VERSION 5.8 ;
BUSBITCHARS "[]" ;
DIVIDERCHAR "/" ;
UNITS
    DATABASE MICRONS 1000 ;
END UNITS

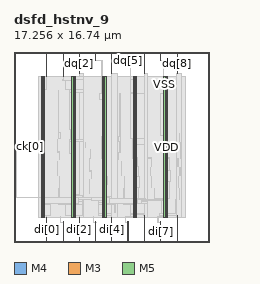
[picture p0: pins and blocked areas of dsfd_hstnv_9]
MACRO dsfd_hstnv_9
  FOREIGN dsfd_hstnv_9 0 0 ;
  CLASS BLOCK ;
  SIZE 17.256 BY 16.74 ;
  PIN ck[0]
    DIRECTION INPUT ;
    USE SIGNAL ;
    PORT
      LAYER M4 ;
        RECT  0 8.4 0.192 8.424 ;
    END
    PORT
      LAYER M4 ;
        RECT  0.156 8.4 0.275 8.424 ;
    END
  END ck[0]
  PIN di[0]
    DIRECTION INPUT ;
    USE SIGNAL ;
    PORT
      LAYER M3 ;
        RECT  2.88 0 2.898 0.144 ;
    END
    PORT
      LAYER M3 ;
        RECT  2.88 0.108 2.898 2.143 ;
    END
  END di[0]
  PIN di[1]
    DIRECTION INPUT ;
    USE SIGNAL ;
    PORT
      LAYER M5 ;
        RECT  4.32 0 4.344 0.192 ;
    END
    PORT
      LAYER M5 ;
        RECT  4.32 0.144 4.344 1.763 ;
    END
  END di[1]
  PIN di[2]
    DIRECTION INPUT ;
    USE SIGNAL ;
    PORT
      LAYER M3 ;
        RECT  5.76 0 5.778 0.144 ;
    END
    PORT
      LAYER M3 ;
        RECT  5.76 0.108 5.778 2.143 ;
    END
  END di[2]
  PIN di[3]
    DIRECTION INPUT ;
    USE SIGNAL ;
    PORT
      LAYER M5 ;
        RECT  7.2 0 7.224 0.192 ;
    END
    PORT
      LAYER M5 ;
        RECT  7.2 0.144 7.224 1.763 ;
    END
  END di[3]
  PIN di[4]
    DIRECTION INPUT ;
    USE SIGNAL ;
    PORT
      LAYER M3 ;
        RECT  8.604 0 8.622 0.144 ;
    END
    PORT
      LAYER M3 ;
        RECT  8.604 0.108 8.622 2.143 ;
    END
  END di[4]
  PIN di[5]
    DIRECTION INPUT ;
    USE SIGNAL ;
    PORT
      LAYER M5 ;
        RECT  10.032 0 10.056 0.192 ;
    END
    PORT
      LAYER M5 ;
        RECT  10.032 0.144 10.056 1.763 ;
    END
  END di[5]
  PIN di[6]
    DIRECTION INPUT ;
    USE SIGNAL ;
    PORT
      LAYER M3 ;
        RECT  11.484 0 11.502 0.144 ;
    END
    PORT
      LAYER M3 ;
        RECT  11.484 0.108 11.502 2.371 ;
    END
  END di[6]
  PIN di[7]
    DIRECTION INPUT ;
    USE SIGNAL ;
    PORT
      LAYER M5 ;
        RECT  12.912 0 12.936 0.192 ;
    END
    PORT
      LAYER M5 ;
        RECT  12.912 0.144 12.936 1.763 ;
    END
  END di[7]
  PIN di[8]
    DIRECTION INPUT ;
    USE SIGNAL ;
    PORT
      LAYER M3 ;
        RECT  14.364 0 14.382 0.144 ;
    END
    PORT
      LAYER M3 ;
        RECT  14.364 0.108 14.382 2.291 ;
    END
  END di[8]
  PIN dq[0]
    DIRECTION OUTPUT ;
    USE SIGNAL ;
    PORT
      LAYER M3 ;
        RECT  2.88 16.596 2.898 16.74 ;
    END
    PORT
      LAYER M3 ;
        RECT  2.88 14.597 2.898 16.62 ;
    END
  END dq[0]
  PIN dq[1]
    DIRECTION OUTPUT ;
    USE SIGNAL ;
    PORT
      LAYER M5 ;
        RECT  4.32 16.548 4.344 16.74 ;
    END
    PORT
      LAYER M5 ;
        RECT  4.32 14.603 4.344 16.592 ;
    END
  END dq[1]
  PIN dq[2]
    DIRECTION OUTPUT ;
    USE SIGNAL ;
    PORT
      LAYER M3 ;
        RECT  5.76 16.596 5.778 16.74 ;
    END
    PORT
      LAYER M3 ;
        RECT  5.76 14.864 5.778 16.62 ;
    END
  END dq[2]
  PIN dq[3]
    DIRECTION OUTPUT ;
    USE SIGNAL ;
    PORT
      LAYER M5 ;
        RECT  7.2 16.548 7.224 16.74 ;
    END
    PORT
      LAYER M5 ;
        RECT  7.2 15.973 7.224 16.592 ;
    END
  END dq[3]
  PIN dq[4]
    DIRECTION OUTPUT ;
    USE SIGNAL ;
    PORT
      LAYER M3 ;
        RECT  8.604 16.596 8.622 16.74 ;
    END
    PORT
      LAYER M3 ;
        RECT  8.604 14.864 8.622 16.62 ;
    END
  END dq[4]
  PIN dq[5]
    DIRECTION OUTPUT ;
    USE SIGNAL ;
    PORT
      LAYER M5 ;
        RECT  10.032 16.548 10.056 16.74 ;
    END
    PORT
      LAYER M5 ;
        RECT  10.032 15.973 10.056 16.592 ;
    END
  END dq[5]
  PIN dq[6]
    DIRECTION OUTPUT ;
    USE SIGNAL ;
    PORT
      LAYER M3 ;
        RECT  11.484 16.596 11.502 16.74 ;
    END
    PORT
      LAYER M3 ;
        RECT  11.484 14.864 11.502 16.62 ;
    END
  END dq[6]
  PIN dq[7]
    DIRECTION OUTPUT ;
    USE SIGNAL ;
    PORT
      LAYER M5 ;
        RECT  12.912 16.548 12.936 16.74 ;
    END
    PORT
      LAYER M5 ;
        RECT  12.912 15.973 12.936 16.592 ;
    END
  END dq[7]
  PIN dq[8]
    DIRECTION OUTPUT ;
    USE SIGNAL ;
    PORT
      LAYER M3 ;
        RECT  14.364 16.596 14.382 16.74 ;
    END
    PORT
      LAYER M3 ;
        RECT  14.364 14.864 14.382 16.62 ;
    END
  END dq[8]
  PIN VDD
    DIRECTION INOUT ;
    USE POWER ;
    PORT
      LAYER M5 ;
        RECT  13.392 2.151 13.512 14.589 ;
        RECT  10.692 2.151 10.812 14.589 ;
        RECT  7.992 2.151 8.112 14.589 ;
        RECT  5.292 2.151 5.412 14.589 ;
        RECT  2.592 2.151 2.712 14.589 ;
    END
  END VDD
  PIN VSS
    DIRECTION INOUT ;
    USE GROUND ;
    PORT
      LAYER M5 ;
        RECT  13.2 2.137 13.32 14.603 ;
        RECT  10.5 2.137 10.62 14.603 ;
        RECT  7.8 2.137 7.92 14.603 ;
        RECT  5.1 2.137 5.22 14.603 ;
        RECT  2.4 2.137 2.52 14.603 ;
    END
  END VSS
  # OT_OBS_CLOSED layer=M5 d_um=1.536 added=0
  OBS
    LAYER RVTN ;
     RECT  2.16 2.16 15.066 2.295 ;
     RECT  2.16 2.565 15.066 2.835 ;
     RECT  2.16 3.105 15.066 3.375 ;
     RECT  2.16 3.645 15.066 3.915 ;
     RECT  2.16 4.185 15.066 4.455 ;
     RECT  2.16 4.725 15.066 4.995 ;
     RECT  2.16 5.265 15.066 5.535 ;
     RECT  2.16 5.805 15.066 6.075 ;
     RECT  2.16 6.345 15.066 6.615 ;
     RECT  2.16 6.885 15.066 7.155 ;
     RECT  2.16 7.425 15.066 7.695 ;
     RECT  2.16 7.965 15.066 8.235 ;
     RECT  2.16 8.505 15.066 8.775 ;
     RECT  2.16 9.045 15.066 9.315 ;
     RECT  2.16 9.585 15.066 9.855 ;
     RECT  2.16 10.125 15.066 10.395 ;
     RECT  2.16 10.665 15.066 10.935 ;
     RECT  2.16 11.205 15.066 11.475 ;
     RECT  2.16 11.745 15.066 12.015 ;
     RECT  2.16 12.285 15.066 12.555 ;
     RECT  2.16 12.825 15.066 13.095 ;
     RECT  2.16 13.365 15.066 13.635 ;
     RECT  2.16 13.905 15.066 14.175 ;
     RECT  2.16 14.445 15.066 14.58 ;
    LAYER RVTP ;
     RECT  2.16 2.295 15.066 2.565 ;
     RECT  2.16 2.835 15.066 3.105 ;
     RECT  2.16 3.375 15.066 3.645 ;
     RECT  2.16 3.915 15.066 4.185 ;
     RECT  2.16 4.455 15.066 4.725 ;
     RECT  2.16 4.995 15.066 5.265 ;
     RECT  2.16 5.535 15.066 5.805 ;
     RECT  2.16 6.075 15.066 6.345 ;
     RECT  2.16 6.615 15.066 6.885 ;
     RECT  2.16 7.155 15.066 7.425 ;
     RECT  2.16 7.695 15.066 7.965 ;
     RECT  2.16 8.235 15.066 8.505 ;
     RECT  2.16 8.775 15.066 9.045 ;
     RECT  2.16 9.315 15.066 9.585 ;
     RECT  2.16 9.855 15.066 10.125 ;
     RECT  2.16 10.395 15.066 10.665 ;
     RECT  2.16 10.935 15.066 11.205 ;
     RECT  2.16 11.475 15.066 11.745 ;
     RECT  2.16 12.015 15.066 12.285 ;
     RECT  2.16 12.555 15.066 12.825 ;
     RECT  2.16 13.095 15.066 13.365 ;
     RECT  2.16 13.635 15.066 13.905 ;
     RECT  2.16 14.175 15.066 14.445 ;
    LAYER M1 ;
     RECT  2.16 2.151 15.066 14.589 ;
    LAYER M2 ;
     RECT  2.16 2.151 5.755 14.589 ;
     RECT  5.755 2.151 6.107 14.859 ;
     RECT  6.107 2.151 8.599 14.589 ;
     RECT  8.599 2.151 9.131 14.859 ;
     RECT  9.131 2.151 11.479 14.589 ;
     RECT  11.479 2.151 11.759 14.859 ;
     RECT  11.759 2.151 14.359 14.589 ;
     RECT  14.359 2.151 14.747 14.859 ;
     RECT  14.747 2.151 15.066 14.589 ;
    LAYER M3 ;
     RECT  9.792 1.723 9.81 2.143 ;
     RECT  12.672 1.723 12.69 2.143 ;
     RECT  4.068 1.723 4.086 2.255 ;
     RECT  6.984 1.723 7.002 2.255 ;
     RECT  9.792 2.143 10.605 2.255 ;
     RECT  12.672 2.143 13.305 2.255 ;
     RECT  2.415 2.143 2.898 2.371 ;
     RECT  5.115 2.143 5.778 2.371 ;
     RECT  7.815 2.143 8.622 2.371 ;
     RECT  12.816 2.255 13.305 2.371 ;
     RECT  10.296 2.255 10.605 2.413 ;
     RECT  11.412 2.371 11.502 2.413 ;
     RECT  7.488 2.371 8.622 2.489 ;
     RECT  10.296 2.413 11.502 2.489 ;
     RECT  12.816 2.371 14.274 2.489 ;
     RECT  2.415 2.371 3.186 3.299 ;
     RECT  8.892 2.641 8.91 3.299 ;
     RECT  4.572 2.371 5.994 3.307 ;
     RECT  10.296 2.489 10.797 3.307 ;
     RECT  7.488 2.489 8.097 3.343 ;
     RECT  9.684 3.307 10.797 3.403 ;
     RECT  11.736 2.641 11.754 3.403 ;
     RECT  2.415 3.299 3.006 3.437 ;
     RECT  7.488 3.343 8.73 3.437 ;
     RECT  9.684 3.403 11.754 3.569 ;
     RECT  3.96 3.307 5.994 3.605 ;
     RECT  9.684 3.569 11.61 3.605 ;
     RECT  7.488 3.437 8.55 3.643 ;
     RECT  12.996 2.489 13.497 3.685 ;
     RECT  14.256 2.489 14.274 3.713 ;
     RECT  12.852 3.685 13.497 3.721 ;
     RECT  6.84 3.643 8.55 3.773 ;
     RECT  7.488 3.773 8.55 3.839 ;
     RECT  10.515 3.605 11.61 3.839 ;
     RECT  12.348 3.721 13.497 3.839 ;
     RECT  13.215 3.839 13.497 3.847 ;
     RECT  7.815 3.839 8.55 4.019 ;
     RECT  5.115 3.605 5.994 4.109 ;
     RECT  5.115 4.109 5.778 4.145 ;
     RECT  3.96 3.605 3.978 4.685 ;
     RECT  9.684 3.605 9.702 4.685 ;
     RECT  12.348 3.839 12.366 4.685 ;
     RECT  14.544 3.721 14.562 4.685 ;
     RECT  10.515 3.839 10.962 4.801 ;
     RECT  7.815 4.019 8.154 5.071 ;
     RECT  13.215 3.847 13.698 5.341 ;
     RECT  6.66 4.261 6.678 5.495 ;
     RECT  4.032 4.801 4.05 5.765 ;
     RECT  7.815 5.071 8.262 5.765 ;
     RECT  9.72 4.801 9.738 5.765 ;
     RECT  10.515 4.801 11.07 5.765 ;
     RECT  12.132 4.801 12.15 5.765 ;
     RECT  14.508 4.801 14.526 5.765 ;
     RECT  6.84 5.611 6.858 6.241 ;
     RECT  13.215 5.341 13.77 6.305 ;
     RECT  6.624 6.241 6.858 6.341 ;
     RECT  12.024 5.881 12.042 6.575 ;
     RECT  14.616 5.881 14.634 6.575 ;
     RECT  10.515 5.765 10.926 6.683 ;
     RECT  3.852 5.881 3.87 7.115 ;
     RECT  9.432 5.881 9.45 7.115 ;
     RECT  6.624 6.341 6.642 7.321 ;
     RECT  7.815 5.765 8.154 7.321 ;
     RECT  10.515 6.683 10.854 7.321 ;
     RECT  12.132 6.691 12.15 7.321 ;
     RECT  13.215 6.305 13.698 7.321 ;
     RECT  14.436 6.691 14.454 7.349 ;
     RECT  6.624 7.321 6.75 7.385 ;
     RECT  7.74 7.321 8.154 7.421 ;
     RECT  10.404 7.321 10.854 7.421 ;
     RECT  11.772 7.321 12.15 7.421 ;
     RECT  13.14 7.321 13.698 7.421 ;
     RECT  5.115 4.145 5.397 7.771 ;
     RECT  3.996 7.231 4.014 7.861 ;
     RECT  9.216 7.231 9.234 7.861 ;
     RECT  9.216 7.861 9.342 7.889 ;
     RECT  3.852 7.861 4.014 7.961 ;
     RECT  6.732 7.385 6.75 8.159 ;
     RECT  13.14 7.421 13.497 8.159 ;
     RECT  11.772 7.421 11.79 8.465 ;
     RECT  7.74 7.421 8.097 8.509 ;
     RECT  10.404 7.421 10.797 8.581 ;
     RECT  6.3 8.311 6.318 8.735 ;
     RECT  14.652 7.393 14.67 8.735 ;
     RECT  4.896 7.771 5.397 8.851 ;
     RECT  9.324 7.889 9.342 8.851 ;
     RECT  3.852 7.961 3.87 9.005 ;
     RECT  4.896 8.851 6.138 9.005 ;
     RECT  10.404 8.581 11.502 9.121 ;
     RECT  7.704 8.509 8.097 9.275 ;
     RECT  9.216 8.851 9.342 9.275 ;
     RECT  13.176 8.159 13.497 9.391 ;
     RECT  14.544 8.851 14.562 9.545 ;
     RECT  3.924 9.085 4.086 9.653 ;
     RECT  5.004 9.005 5.397 9.931 ;
     RECT  7.776 9.275 8.097 12.559 ;
     RECT  6.12 9.005 6.138 13.055 ;
     RECT  7.524 12.559 8.097 13.055 ;
     RECT  9.324 9.275 9.342 13.055 ;
     RECT  10.296 9.121 11.502 13.055 ;
     RECT  12.888 9.391 13.497 13.055 ;
     RECT  4.932 9.931 5.397 13.171 ;
     RECT  10.296 13.055 10.797 13.171 ;
     RECT  3.924 9.653 3.942 13.325 ;
     RECT  14.76 9.661 14.778 13.325 ;
     RECT  2.415 3.437 2.697 13.441 ;
     RECT  4.932 13.171 6.102 13.441 ;
     RECT  4.536 13.441 6.102 14.285 ;
     RECT  10.26 13.171 10.797 14.327 ;
     RECT  13.14 13.055 13.497 14.327 ;
     RECT  2.415 13.441 2.898 14.597 ;
     RECT  5.115 14.285 6.102 14.597 ;
     RECT  7.74 13.055 8.097 14.597 ;
     RECT  10.26 14.327 10.605 14.597 ;
     RECT  13.14 14.327 13.305 14.597 ;
     RECT  9.108 13.171 9.126 14.836 ;
     RECT  11.736 13.063 11.754 14.836 ;
     RECT  14.724 13.441 14.742 14.836 ;
     RECT  5.76 14.597 6.102 14.864 ;
     RECT  8.604 14.836 9.126 14.864 ;
     RECT  11.484 14.836 11.754 14.864 ;
     RECT  14.364 14.836 14.742 14.864 ;
     RECT  7.74 14.597 7.758 16.013 ;
     RECT  10.26 14.597 10.278 16.013 ;
     RECT  13.14 14.597 13.158 16.013 ;
    LAYER M4 ;
     RECT  0.229 3.888 2.408 3.912 ;
     RECT  2.408 2.148 2.512 14.592 ;
     RECT  2.512 2.418 2.704 14.322 ;
     RECT  4.057 1.728 4.355 1.752 ;
     RECT  2.704 3.408 5.108 3.912 ;
     RECT  4.309 14.256 5.108 14.28 ;
     RECT  5.108 2.148 5.212 14.592 ;
     RECT  5.212 2.418 5.404 14.322 ;
     RECT  5.404 3.408 5.681 3.912 ;
     RECT  5.681 3.744 6.829 3.912 ;
     RECT  6.973 1.728 7.235 1.752 ;
     RECT  7.189 15.984 7.769 16.008 ;
     RECT  6.829 3.648 7.808 3.912 ;
     RECT  7.808 2.148 7.912 14.592 ;
     RECT  7.912 2.418 8.104 14.322 ;
     RECT  8.104 3.408 8.381 3.912 ;
     RECT  9.781 1.728 10.067 1.752 ;
     RECT  10.021 15.984 10.289 16.008 ;
     RECT  8.381 3.408 10.508 3.864 ;
     RECT  10.508 2.148 10.612 14.592 ;
     RECT  10.612 2.418 10.804 14.322 ;
     RECT  10.804 3.408 10.865 3.864 ;
     RECT  10.865 3.408 11.261 3.72 ;
     RECT  12.661 1.728 12.947 1.752 ;
     RECT  12.901 15.984 13.169 16.008 ;
     RECT  11.261 3.696 13.208 3.72 ;
     RECT  13.208 2.148 13.312 14.592 ;
     RECT  13.312 2.418 13.504 14.322 ;
    LAYER M5 ;
     RECT  2.4 2.137 2.52 2.151 ;
     RECT  5.1 2.137 5.22 2.151 ;
     RECT  7.8 2.137 7.92 2.151 ;
     RECT  10.5 2.137 10.62 2.151 ;
     RECT  13.2 2.137 13.32 2.151 ;
     RECT  0.24 3.877 0.264 8.435 ;
     RECT  5.1 2.151 5.412 14.245 ;
     RECT  2.4 2.151 2.712 14.589 ;
     RECT  4.32 14.245 5.412 14.589 ;
     RECT  7.8 2.151 8.112 14.589 ;
     RECT  10.5 2.151 10.812 14.589 ;
     RECT  13.2 2.151 13.512 14.589 ;
     RECT  2.4 14.589 2.52 14.603 ;
     RECT  4.32 14.589 5.22 14.603 ;
     RECT  7.8 14.589 7.92 14.603 ;
     RECT  10.5 14.589 10.62 14.603 ;
     RECT  13.2 14.589 13.32 14.603 ;
  END
END dsfd_hstnv_9
END LIBRARY
